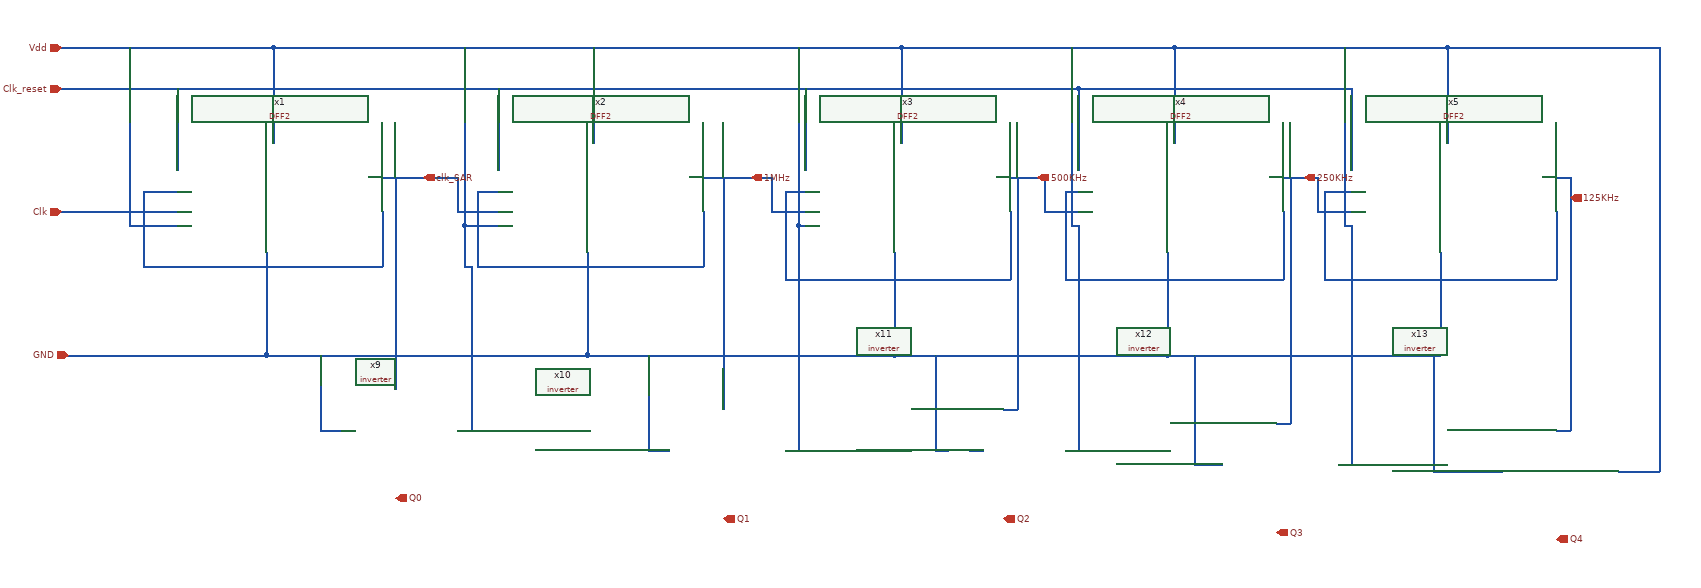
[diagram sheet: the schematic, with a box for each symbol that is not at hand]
v {xschem version=3.4.8RC file_version=1.3}
G {}
K {}
V {}
S {}
F {}
E {}
N -820 -70 -650 -70 {lab=Clk}
N -700 -100 -650 -100 {lab=#net1}
N -700 -100 -700 10 {lab=#net1}
N -700 10 -350 10 {lab=#net1}
N -350 -70 -350 10 {lab=#net1}
N -520 -10 -520 140 {lab=GND}
N -810 140 -520 140 {lab=GND}
N -510 -310 -510 -170 {lab=Vdd}
N -820 -310 -510 -310 {lab=Vdd}
N -350 -120 -240 -120 {lab=clk_SAR}
N -240 -120 -240 -70 {lab=clk_SAR}
N -240 -70 -180 -70 {lab=clk_SAR}
N -520 140 -50 140 {lab=GND}
N -50 -10 -50 140 {lab=GND}
N -50 140 400 140 {lab=GND}
N 400 -10 400 140 {lab=GND}
N 120 -120 220 -120 {lab=1MHz}
N 220 -70 270 -70 {lab=1MHz}
N 220 -120 220 -70 {lab=1MHz}
N 120 -70 120 10 {lab=#net2}
N -210 10 120 10 {lab=#net2}
N -210 -100 -210 10 {lab=#net2}
N -210 -100 -180 -100 {lab=#net2}
N 570 -70 570 30 {lab=#net3}
N 240 30 570 30 {lab=#net3}
N 240 -100 240 30 {lab=#net3}
N 240 -100 270 -100 {lab=#net3}
N -510 -310 410 -310 {lab=Vdd}
N 410 -310 410 -170 {lab=Vdd}
N -40 -300 -40 -170 {lab=Vdd}
N -40 -310 -40 -300 {lab=Vdd}
N 570 -120 620 -120 {lab=500KHz}
N 620 -120 620 -70 {lab=500KHz}
N 620 -70 670 -70 {lab=500KHz}
N 970 -70 970 30 {lab=#net4}
N 650 30 970 30 {lab=#net4}
N 650 -100 650 30 {lab=#net4}
N 650 -100 670 -100 {lab=#net4}
N 410 -310 810 -310 {lab=Vdd}
N 810 -310 810 -170 {lab=Vdd}
N 400 140 800 140 {lab=GND}
N 800 -10 800 140 {lab=GND}
N -720 -50 -650 -50 {lab=Vdd}
N -720 -310 -720 -50 {lab=Vdd}
N -230 -50 -190 -50 {lab=Vdd}
N -230 -310 -230 -50 {lab=Vdd}
N 260 -50 270 -50 {lab=Vdd}
N 260 -310 260 -50 {lab=Vdd}
N 660 -50 670 -50 {lab=Vdd}
N 660 -310 660 -50 {lab=Vdd}
N 670 -250 670 -130 {lab=Clk_reset}
N -820 -250 670 -250 {lab=Clk_reset}
N 270 -250 270 -130 {lab=Clk_reset}
N -180 -250 -180 -130 {lab=Clk_reset}
N -650 -250 -650 -130 {lab=Clk_reset}
N 970 -120 1020 -120 {lab=250KHz}
N 1020 -120 1020 -70 {lab=250KHz}
N 1020 -70 1070 -70 {lab=250KHz}
N 1030 -100 1070 -100 {lab=#net5}
N 1030 -100 1030 30 {lab=#net5}
N 1030 30 1370 30 {lab=#net5}
N 1370 -70 1370 30 {lab=#net5}
N 810 -310 1210 -310 {lab=Vdd}
N 1210 -310 1210 -170 {lab=Vdd}
N 1070 -250 1070 -130 {lab=Clk_reset}
N 670 -250 1070 -250 {lab=Clk_reset}
N 800 140 1200 140 {lab=GND}
N 1200 -10 1200 140 {lab=GND}
N 1060 -50 1070 -50 {lab=Vdd}
N 1060 -310 1060 -50 {lab=Vdd}
N -240 250 -220 250 {lab=Vdd}
N -440 250 -410 250 {lab=GND}
N -440 140 -440 250 {lab=GND}
N -330 -120 -330 190 {lab=clk_SAR}
N 150 -120 150 220 {lab=1MHz}
N 40 280 70 280 {lab=GND}
N 40 140 40 280 {lab=GND}
N 260 -50 260 280 {lab=Vdd}
N 240 280 260 280 {lab=Vdd}
N 510 280 530 280 {lab=#net6}
N 670 -50 670 280 {lab=Vdd}
N 650 280 670 280 {lab=Vdd}
N 460 280 480 280 {lab=GND}
N 460 140 460 280 {lab=GND}
N 580 -120 580 220 {lab=500KHz}
N 560 220 580 220 {lab=500KHz}
N 980 -120 980 240 {lab=250KHz}
N 960 240 980 240 {lab=250KHz}
N 840 140 840 300 {lab=GND}
N 840 300 880 300 {lab=GND}
N 1050 300 1070 300 {lab=Vdd}
N 1070 -50 1070 300 {lab=Vdd}
N 1190 140 1190 310 {lab=GND}
N 1190 310 1280 310 {lab=GND}
N 1280 310 1290 310 {lab=GND}
N 1210 -310 1520 -310 {lab=Vdd}
N 1520 -310 1520 310 {lab=Vdd}
N 1460 310 1520 310 {lab=Vdd}
N 1370 -120 1390 -120 {lab=125KHz}
N 1390 -120 1390 250 {lab=125KHz}
N 1370 250 1390 250 {lab=125KHz}
N -190 -50 -180 -50 {lab=Vdd}
N -220 10 -220 250 {lab=Vdd}
N -230 10 -220 10 {lab=Vdd}
N -230 -50 -230 10 {lab=Vdd}
C {/home/jetha/Projects/sky130/SAR_ADC/D_flipflop/DFF2.sym} -500 -90 0 0 {name=x1}
C {/home/jetha/Projects/sky130/SAR_ADC/D_flipflop/DFF2.sym} -30 -90 0 0 {name=x2}
C {/home/jetha/Projects/sky130/SAR_ADC/D_flipflop/DFF2.sym} 420 -90 0 0 {name=x3}
C {/home/jetha/Projects/sky130/SAR_ADC/D_flipflop/DFF2.sym} 820 -90 0 0 {name=x4}
C {/home/jetha/Projects/sky130/SAR_ADC/D_flipflop/DFF2.sym} 1220 -90 0 0 {name=x5}
C {/home/jetha/Projects/sky130/SAR_ADC/inverter/inverter.sym} -490 210 1 0 {name=x9}
C {/home/jetha/Projects/sky130/SAR_ADC/inverter/inverter.sym} -10 240 1 0 {name=x10}
C {/home/jetha/Projects/sky130/SAR_ADC/inverter/inverter.sym} 400 240 1 0 {name=x11}
C {/home/jetha/Projects/sky130/SAR_ADC/inverter/inverter.sym} 800 260 1 0 {name=x12}
C {/home/jetha/Projects/sky130/SAR_ADC/inverter/inverter.sym} 1210 270 1 0 {name=x13}
C {opin.sym} -330 350 1 0 {name=p1 lab=Q0}
C {ipin.sym} -820 -310 0 0 {name=p3 lab=Vdd}
C {ipin.sym} -820 -250 0 0 {name=p2 lab=Clk_reset}
C {ipin.sym} -820 -70 0 0 {name=p4 lab=Clk}
C {ipin.sym} -810 140 0 0 {name=p5 lab=GND}
C {opin.sym} 150 380 1 0 {name=p6 lab=Q1}
C {opin.sym} 560 380 1 0 {name=p7 lab=Q2}
C {opin.sym} 960 400 1 0 {name=p8 lab=Q3}
C {opin.sym} 1370 410 1 0 {name=p9 lab=Q4}
C {opin.sym} -290 -120 1 0 {name=p10 lab=clk_SAR}
C {opin.sym} 190 -120 1 0 {name=p11 lab=1MHz}
C {opin.sym} 610 -120 1 0 {name=p12 lab=500KHz}
C {opin.sym} 1000 -120 1 0 {name=p13 lab=250KHz}
C {opin.sym} 1390 -90 0 0 {name=p14 lab=125KHz}
